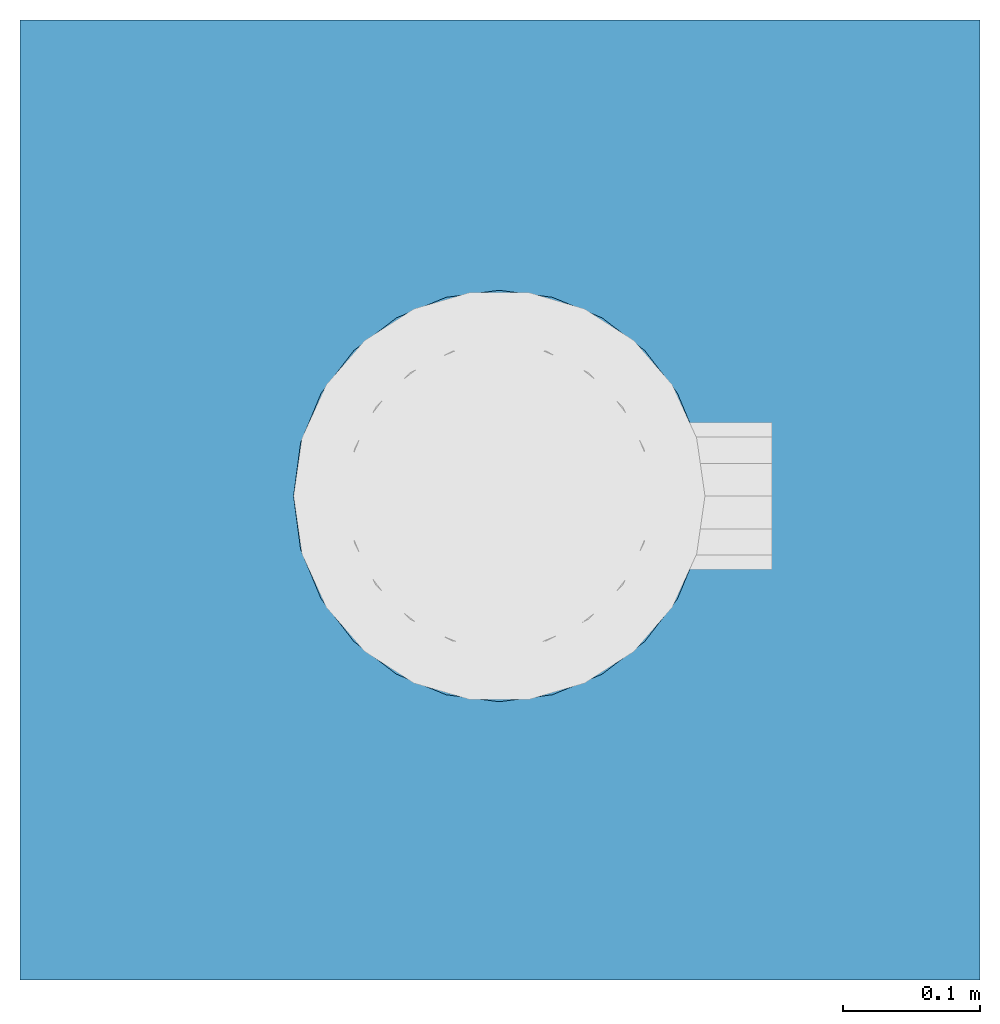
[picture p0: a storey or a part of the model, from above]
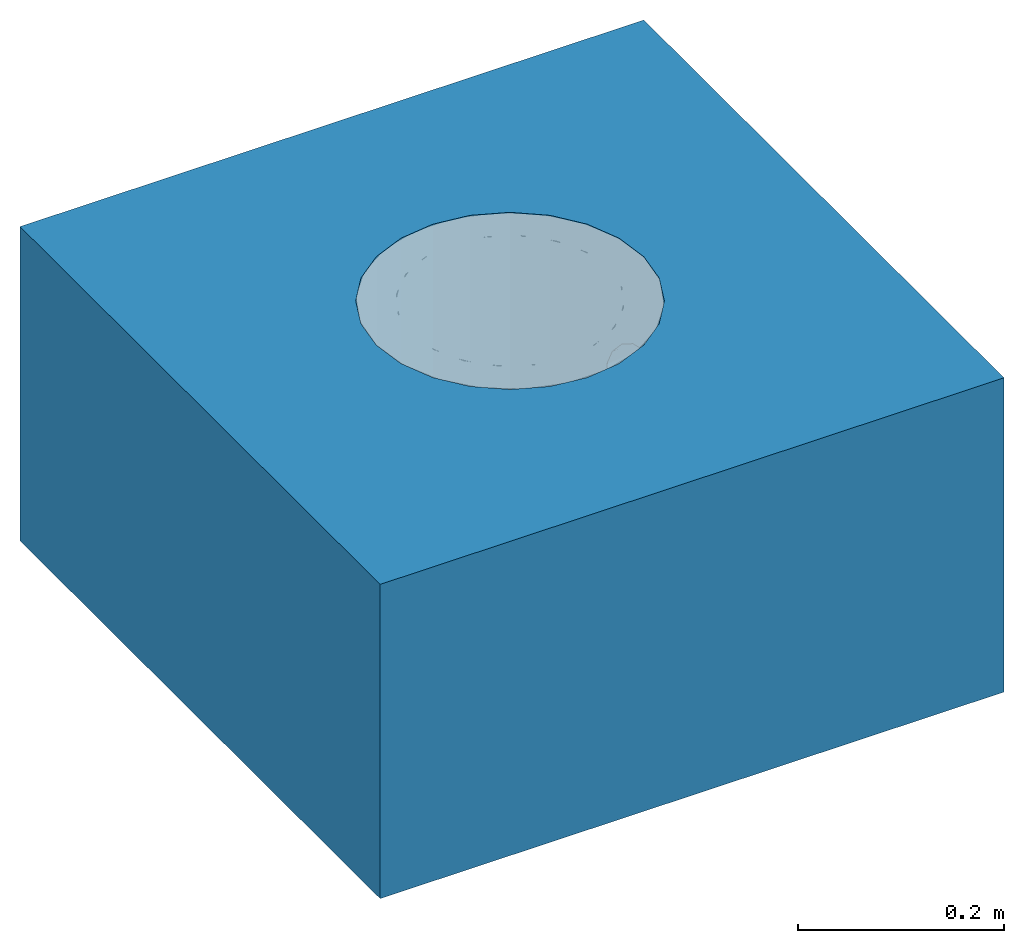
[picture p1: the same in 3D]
Properties of the parts of a building model (IFC2X3)

# File
Description: ViewDefinition [CoordinationView]
File name: Project Number
Time: 2014-10-13T17:51:27
Written by: The EXPRESS Data Manager Version 5.01.0100.02.64mod : 6 Jun 2012
Made in: 20130308_1515(x64) - Exporter 2014.0.2013.0308 - Default UI
Comment: STEP Physical File produced by: The EXPRESS Data Manager Version 5.01.0100.02.64mod : 6 Jun 2012 * Module: EDMstepFileFactory/EDMstandAlone * Creation date: Mon Oct 13 17:51:27 2014 * Host: IN-BLR-PC-0012 * Database: C:\Users\pponnur\AppData\Local\Temp\{C7AAFFFB-E95D-4DFA-BF40-01A3D701A562}\ifc * Database version: 5507 * Database creation date: Mon Oct 13 17:51:26 2014 * Schema: IFC2X3 * Model: DataRepository.ifc * Model creation date: Mon Oct 13 17:51:26 2014 * Header model: DataRepository.ifc_HeaderModel * Header model creation date: Mon Oct 13 17:51:26 2014 * EDMuser: sdai-user * EDMgroup: sdai-group * License ID and type: 5605 : Permanent license. Expiry date: * EDMstepFileFactory options: 020000

# IfcProject, Project Number
LongName: Project Name; Phase: Project Status

# IfcSite, Default
RefLatitude: 42, 21, 30, 344238; RefLongitude: -71, -3, -35, -194702; RefElevation: 0 mm

# IfcBuilding
Pset_BuildingCommon - NumberOfStoreys: 1
Other - Project Issue Date: Issue Date; Project Number: Project Number; Project Status: Project Status; Project Address: Enter address here; Project Name: Project Name; Client Name: Owner

# IfcBuildingStorey, Level 1
LongName: Level 1; Elevation: 0 mm
Constraints - Elevation Base: Project Base Point; Elevation: 0 mm
Graphics - Line Weight: 1; Line Pattern: Grid Line 1/2"; Symbol at End 1 Default: no; Color: 0; Symbol: Level Head - Circle: Level Head - Circle; Symbol at End 2 Default: yes
Dimensions - Computation Height: 0 mm
Identity Data - Name: Level 1; Building Story: yes; Structural: no

# IfcFlowTerminal: 408085 Body / 408242 Top, ACO BD Gully 218 Telescopic - Vinyl Top - Horizontal Outlet with Location Flange - 222 mm:408085 Body / 408242 Top:198728
In: Level 1
Material: Stainless Steel AISI 304, Rubber, Nitrile
Materials and Finishes - Material: Stainless Steel AISI 304
Model Properties - Raising Piece Product Code 408209: NA; Product Code 408220: Foul Air Trap - Stainless Steel 304; Grating Product Code 97148: Load Class M125 (EN 1253) - Ladder Grating - Plain - Stainless steel 1.4301 (EN 10088) - 222mm Ø; Product Code 408221: Foul Air Trap Support Ring – Nitrile; Grating Product Code 97153: Load Class L15 (EN 1253) - Perforated Grating - Plain - Stainless steel 1.4301 (EN 10088) - 222mm Ø; Product Code 408225: Friction Ring Installation Set - Nitrile; Product Code 408223: Silt Basket - Stainless Steel 304; Grating Product Code 97156: Load Class M125 (EN 1253) - Slot Grating - Plain - Stainless steel 1.4301 (EN 10088) - 222mm Ø
Mechanical - System Classification: Sanitary
Identity Data - Mark: 6; Water Mark 1: This file is the property of ACO Technologies PLC; E-mail Technical: abdtechnical@aco.co.uk; Watermarked By: www.acobd.com; E-mail Sales: abdcommercial@aco.co.uk; Website: www.acobd.com; Address: ACO Business Centre, Caxton Road, Bedford, MK41 0LF; Fax: +44 (0)1462 851490; Water Mark 2: This file is water marked and users are prohibited to reproduce, adapt, distribute this information; Telephone: +44 (0)1462 816666; Water Marked With: BIM Manager Premium Suite; Manufacturer: ACO Building Drainage
Construction - 97153 - 222mm Ø - Perforated Grating - Plain - Stainless steel 304: no; 97148 - 222mm Ø - Ladder Grating - Plain - Stainless steel 304: no; 97156 - 222mm Ø - Slot Grating - Plain - Stainless steel 304: no; 408220 - Foul Air Trap & 408221 - Foul Air Trap Support Ring: yes; 408223 - Silt Basket: yes
Constraints - Level: Level: Level 1
Phasing - Phase Created: New Construction
Dimensions - Rasing Piece Height: 500 mm; Floor To Gully Height: 68 mm; FFL To Gully Top Height: 68 mm; Floor Void End: -221 mm
Other - Raising Piece Detail: no; 408209 - Raising Piece with Location Flange: no
Pset_ManufacturerTypeInformation - Manufacturer: ACO Building Drainage
General - Load Class: A15 - C250 (EN 1253); Installation guidelines: http://issuu.com/acobuildingdrainage/docs/120820112708-138bdc871b784edfa2b6b8197acfd881?e=0; Gully Top Size (mm): 242mm Diameter; Product Type: Point drainage; Foul Air Trap Seal Recycled Material Content: 0%; Gully top Grate size (mm): 222; Gully Top Product Description: ACO Gully 218 Telescopic Top for Vinyl Floor; Flow Rate (l/s): 4.4 - 5.5 l/s; NBS Specification: R11 ABOVE GROUND FOUL DRAINAGE SYSTEMS : Clause 315; Gully Top Product Code: 408242; Gully Recycled Material Content: 20 - 30 %; Gully Colour: passivated stainless steel surface ( matt grey); Foul Air Trap Seal Material: NBR; Price: POA - contact ACO; Gully Product Code: 408085; Gully Recyclable: Fully recyclable; Product Standard: EN 1253; Maintenance guidelines: http://issuu.com/acobuildingdrainage/docs/120820112708-138bdc871b784edfa2b6b8197acfd881?e=0; Foul Air Trap Seal Colour: Black; Gully Flange Type: Location; Foul Air Trap Seal Recyclable: Fully recyclable; Gully Product Description: ACO Gully 218 Telescopic Flange Type DN110 Horizontal with Foul Air Trap; Outlet Diameter (mm): 110; Product Range: ACO Gully 218; Gully Material: Stainless Steel Grade 304 (EN 1253)

# IfcOpeningElement: Recess
In: Level 1
Constraints - Room Bounding: yes; Level: Level: Level 1; Height Offset From Level: 0 mm; Related to Mass: no
Structural - Enable Analytical Model: no; Structural: no
Dimensions - Area: 5.27432 ft2; Perimeter: 2800 mm; Thickness: 372.8 mm; Volume: 5.88202 ft3
Phasing - Phase Created: New Construction
Analytical Properties - Thermal mass: 53301.1; Roughness: 3; Thermal Resistance (R): 0.641509; Heat Transfer Coefficient (U): 1.55882; Absorptance: 0.7
Identity Data - Assembly Code: B1010; Assembly Description: Floor Construction
Graphics - Coarse Scale Fill Color: 0
Construction - Default Thickness: 372.8 mm; Function: Interior

# IfcSlab: Floor:Generic - 12", Floor:Generic - 12":184145
In: Level 1
PredefinedType: FLOOR; Material: Plywood, Sheathing 68 mm, Default Floor 304.8 mm
Constraints - Room Bounding: yes; Level: Level: Level 1; Height Offset From Level: 0 mm; Related to Mass: no
Structural - Enable Analytical Model: no; Structural: no
Dimensions - Area: 5.27432 ft2; Perimeter: 2800 mm; Thickness: 372.8 mm; Volume: 5.88202 ft3
Phasing - Phase Created: New Construction
Pset_SlabCommon - Reference: Generic - 12"; IsExternal: no; LoadBearing: yes; ThermalTransmittance: 1.55882 kg/K/s3
Analytical Properties - Thermal mass: 53301.1; Roughness: 3; Thermal Resistance (R): 0.641509; Heat Transfer Coefficient (U): 1.55882; Absorptance: 0.7
Identity Data - Assembly Code: B1010; Assembly Description: Floor Construction
Graphics - Coarse Scale Fill Color: 0
Construction - Default Thickness: 372.8 mm; Function: Interior
